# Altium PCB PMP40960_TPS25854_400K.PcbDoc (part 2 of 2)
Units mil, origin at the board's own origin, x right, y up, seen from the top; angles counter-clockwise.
Board outline 1968.5 x 1377.95 mil, 4 copper layers (Top Layer, Signal Layer 1, Signal Layer 2, Bottom Layer), stack 64.835 mil thick; 72 components, 24 nets, 181 pads, 267 vias.

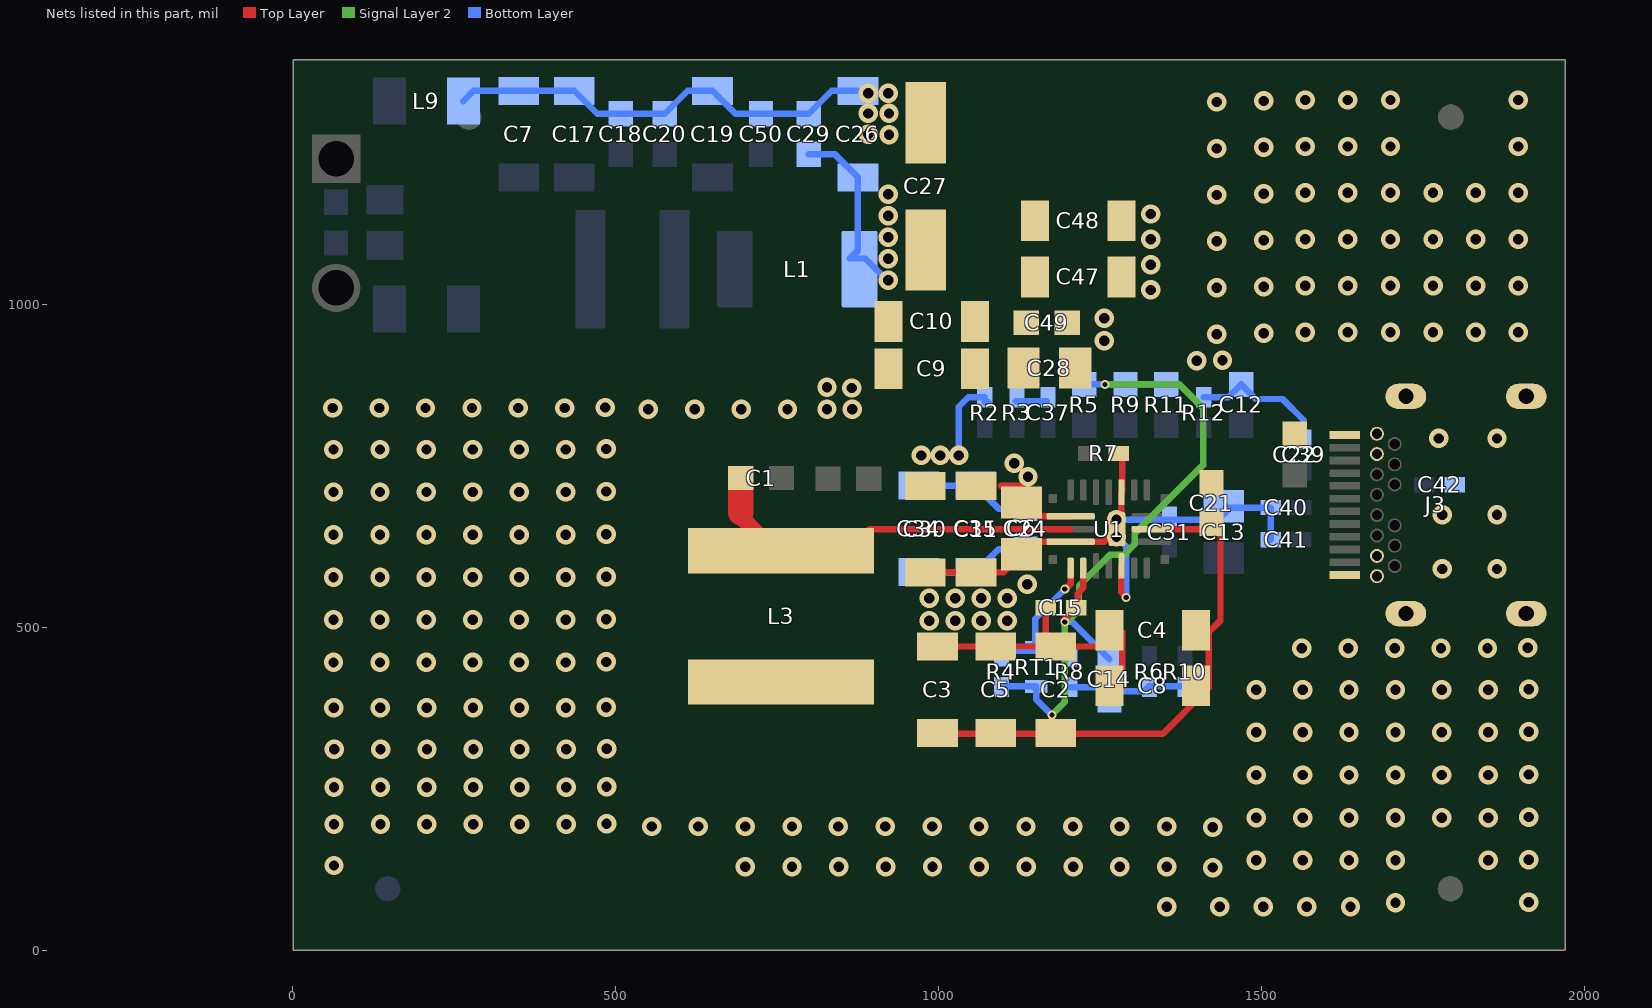
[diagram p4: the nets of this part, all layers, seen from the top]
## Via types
v1: diameter 30, hole 16, Top Layer to Bottom Layer, 246 vias
v2: diameter 14, hole 8, Top Layer to Bottom Layer, 21 vias

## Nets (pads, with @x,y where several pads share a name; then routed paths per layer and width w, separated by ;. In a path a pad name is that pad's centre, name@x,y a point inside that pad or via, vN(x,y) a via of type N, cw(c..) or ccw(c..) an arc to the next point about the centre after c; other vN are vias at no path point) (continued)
PGND: C2.2 C3.2 C4.2 C5.2 C6.2 C7.2 C8.2 C9.2 C10.2 C11.2 C12.2 C13.2 C14.2 C15.2 C17.2 C18.2 C19.2 C20.2 C21.2 C22.2 C24.2 C26.2 C27.2 C28.2 C29.2 C30.2 C31.2 C34.2 C35.2 C37.2 C39.2 C40.2 C41.2 C42.2 C47.2 C48.2 C49.2 C50.2 J3.A1 J3.A12 J3.B1 J3.B12 J3.M1 J3.M2 J3.S1 J3.S2 J3.S3 J3.S4 L9.2 R3.1 R6.1 R7.1 R8.1 R10.1 R12.1 U1.6 U1.16 U1.24 U1.25 | length 2662.7
  Top Layer w10: C30.2@979.01,584.76 1057.94,584.76 C11.2@1058.01,584.83 1100.16,584.83 C6.2@1128.01,612.69 1147.33,632.01 U1.24@1203.96,632.01 1256.13,632.01 U1.25@1275.81,651.69 1282.7,658.58 U1.16@1282.7,708.78 1284,710.08 1284,763.33 R7.1@1278.64,768.69 ; C3.2@998,469.93 C5.2@1088,469.93 C2.2@1157,469.93 ; C6.2@1143.98,598.1 C6.2@1153.56,607.68 ; C15.2@1165.38,530 1165.38,478.31 C2.2@1157,469.93 ; U1.6@1282.7,594.61 1282.7,553.97 1283.98,552.69 ; R7.1@1282.83,768.69 1282.83,771.24 1282.98,771.39 R7.1@1282.98,768.69 ; C8.2@1284.07,406 1284.07,492 1262,469.93 C2.2@1180.93,469.93 C2.2@1157,469.93
  Signal Layer 2 w10: v2@1290,543.72 v2(1290,546)
  Bottom Layer w10: L9.2@264.01,1314.01 279.94,1329.94 C7.2@349.81,1329.94 C17.2@435.81,1329.94 471.24,1294.5 C18.2@507.81,1294.5 C20.2@575.81,1294.5 611.24,1329.94 C19.2@649.81,1329.94 685.24,1294.5 C50.2@724.81,1294.5 C29.2@798.81,1294.5 834.24,1329.94 C26.2@874.81,1329.94 ; C34.2@969,585.07 C35.2@1057,585.07 1092.43,620.5 C24.2@1134,620.5 ; R3.1@1119,849.62 C37.2@1167,849.62 ; R8.1@1202,406.76 1256.75,406.76 1263,400.5 1317.13,400.5 1325,408.38 R10.1@1380,408.38 ; v1(1275.01,639.69) 1290,624.71 v2(1290,546) ; v1(1275,666) 1432,666 C13.2@1451,685 ; R12.1@1410,855.64 1448.14,855.64 C12.2@1468,875.5 1490.5,853 1532,853 1565,820 C39.2@1565,790.24 ; C13.2@1445,687 1447,685 C13.2@1451,685 ; C41.2@1513.88,635 C40.2@1513.88,685 C13.2@1451,685
  other v1: 1352.9,67.01 1434.59,67.01 1502.11,67.01 1569.63,67.01 1637.15,67.01 1706.8,73.27 1913,74.07 1424,127.76 700.21,129.01 772.73,129.01 845.25,129.01 917.78,129.01 990.3,129.01 1062.82,129.01 1135.34,129.01 1207.86,129.01 1280.24,129.23 1352.9,129.01 63.94,131.01 1491.17,139.2 1563.05,139.2 1634.92,139.2 1706.8,139.2 1850.55,139.2 1913,140 1424,190 555.67,191.25 627.55,191.25 700.21,191.25 772.88,191.25 844.26,191.25 916.92,191.25 989.59,191.25 1062.25,191.25 1134.91,191.25 1207.58,191.25 1280.24,191.25 1352.9,191.25 63.94,195.01 135.81,195.01 207.69,195.01 279.56,195.01 351.44,195.01 423.31,195.01 485.76,195.8 1491.17,205.13 1563.05,205.13 1634.92,205.13 1706.8,205.13 1778.67,205.13 1850.55,205.13 1913,205.93 63.94,252.01 135.81,252.01 207.69,252.01 279.56,252.01 351.44,252.01 423.31,252.01 485.76,252.8 1491.17,271.07 1563.05,271.07 1634.92,271.07 1706.8,271.07 1778.67,271.07 1850.55,271.07 1913,271.86 64.06,311.01 135.94,311.01 207.81,311.01 279.69,311.01 351.56,311.01 423.44,311.01 485.89,311.8 1491.17,337 1563.05,337 1634.92,337 1706.8,337 1778.67,337 1850.55,337 1913,337.79 63.48,375.01 135.36,375.01 207.23,375.01 279.11,375.01 350.98,375.01 422.86,375.01 485.31,375.8 1491.17,402.93 1563.05,402.93 1634.92,402.93 1706.8,402.93 1778.67,402.93 1850.55,402.93 1913,403.72 63.17,445.27 135.05,445.27 206.92,445.27 278.8,445.27 350.67,445.27 422.55,445.27 485,446.07 1561.69,467.01 1633.56,467.01 1705.44,467.01 1777.31,467.01 1849.19,467.01 1911.64,467.8 985.01,510 1025.33,510 1065.67,510 1106,510 63.17,511.2 135.05,511.2 206.92,511.2 278.8,511.2 350.67,511.2 422.55,511.2 485,512 985.01,544.69 1025.35,544.69 1065.68,544.69 1106.01,544.69 1137.01,566.38 63.17,577.13 135.05,577.13 206.92,577.13 278.8,577.13 350.67,577.13 422.55,577.13 485,577.93 1779,590 1864,590 63.17,643.07 135.05,643.07 206.92,643.07 278.8,643.07 350.67,643.07 422.55,643.07 485,643.86 1779,674 1864,674 63.17,709 135.05,709 206.92,709 278.8,709 350.67,709 422.55,709 485,709.79 63.17,774.93 135.05,774.93 206.92,774.93 278.8,774.93 350.67,774.93 422.55,774.93 485,775.72 1774,792 1864,792 550.25,837 622.12,837 694,837 765.88,837 827,837 865.97,837 61.81,839.01 133.69,839.01 205.56,839.01 277.44,839.01 349.31,839.01 421.19,839.01 483.64,839.8 865,870 827,871 1399,912 1439,913 1256,943 1430,953.25 1503.13,955.01 1567.21,956.38 1633.14,956.38 1699.07,956.38 1765,956.38 1830.93,956.38 1896.86,956.38 1256,978 1328,1021.83 1430,1025.12 1503.13,1026.89 1567.21,1028.25 1633.14,1028.25 1699.07,1028.25 1765,1028.25 1830.93,1028.25 1896.86,1028.25 1328,1061 1430,1097 1503.13,1098.76 1328,1100.17 1567.21,1100.12 1633.14,1100.12 1699.07,1100.12 1765,1100.12 1830.93,1100.12 1896.86,1100.12 1328,1139.33 1430,1168.88 1503.13,1170.64 1567.21,1172 1633.14,1172 1699.07,1172 1765,1172 1830.93,1172 1896.86,1172 1430,1240.75 1503.13,1242.51 1567.21,1243.88 1633.14,1243.88 1699.07,1243.88 1896.86,1243.88 922.81,1262.01 890.81,1263.01 890.81,1295.01 922.81,1295.01 1430,1312.62 1503.13,1314.39 1567.21,1315.75 1633.14,1315.75 1699.07,1315.75 1896.86,1315.75 890.81,1326.01 921.81,1326.01
SENS: C2.1 C3.1 C4.1 C5.1 C8.1 C14.1 C15.1 C21.1 L3.2 R4.2 R5.1 R9.1 R11.1 RT1.2 U1.3 U1.11 | length 2017.2
  Top Layer w10: C3.1@1003.01,335.07 1165,335.07 1165.07,335 1346.93,335 1417.93,406 1417.93,492 1436,510.07 1436,648.88 1433.18,651.69 U1.11@1328.96,651.69 ; v2(1175,364) 1175,342 C2.1@1180.93,336.07 ; v2(1195,508) 1195,509.62 1193.62,511 C15.1@1212.62,530 ; C15.1@1215.01,536.99 1215.01,551.69 ; 1215.43,552.27 1221.96,558.8 1221.96,559.26 1223.64,560.94 U1.3@1223.64,591.16
  Signal Layer 2 w10: v2(1175,364) 1195,384 v2(1195,508) 1199,508 1217,526 1217,564 1264.69,611.69 1286.61,611.69 1303.01,628.09 1303.01,644.73 1409,750.72 1409,839 1372.5,875.5 v2(1257,875.5)
  Bottom Layer w10: R4.2@1102.38,403 R4.2@1097.19,408.19 ; RT1.2@1150,403 RT1.2@1151,402 ; v2(1175,364) 1151,388 RT1.2@1151,402 ; v2(1195,508) 1206.5,508 C14.1@1264,450.5 ; R5.1@1225,875.5 v2(1257,875.5) R9.1@1289,875.5 R11.1@1352,875.5 ; R4.2@1097.19,408.19 1094.81,408.19 1096,409.38 R4.2@1097.19,408.19 ; R4.2@1097.19,408.19 RT1.2@1151,408.19 RT1.2@1151,402
SW: C1.1 L3.1 | length 536.6
  Top Layer w10: L3.1@748.2,645.27 L3.1@780.01,645.27 ; L3.1@880.01,638.27 893.44,651.69 1203.96,651.69
  Top Layer w19.68: L3.1@799.45,640.27 L3.1@821.61,640.27
  Top Layer w25: 693.52,677.2 690.01,673.69 737.25,626.46 L3.1@779.01,626.46
  Top Layer w40: 693.52,677.2 C1.1@693.52,716.84
TS: R4.1 R8.2 RT1.1 U1.2 | length 264.2
  Top Layer w10: v2(1195.01,558.69) 1196.39,558.69 1197.01,559.31 1197.01,559.56 1203.96,566.51 U1.2@1203.96,591.16
  Bottom Layer w10: R4.1@1096,456.62 1102.38,463 RT1.1@1150,463 ; v2(1195.01,558.69) 1149.32,513 1149.32,463.68 RT1.1@1150,463 ; R8.2@1202,454 1193,463 RT1.1@1150,463
VIN: C6.1 C9.1 C10.1 C11.1 C24.1 C26.1 C27.1 C28.1 C29.1 C30.1 C34.1 C35.1 C47.1 C48.1 C49.1 L1.2 R2.2 U1.22 | length 698.6
  Top Layer w10: 1095.69,718.98 1126.66,718.98 ; C6.1@1143.01,683.19 1154.83,671.38 U1.22@1203.96,671.38
  Bottom Layer w10: C29.1@798.81,1231.51 839.38,1231.51 C26.1@874.81,1196.08 874.81,1083.01 862.31,1070.51 886.09,1070.51 v1@920.81,1035.78 ; C34.1@969,718.93 C35.1@1057,718.93 1092.43,683.5 C24.1@1134,683.5 ; v1(1031.01,765.69) 1031.01,841.08 1045.57,855.64 R2.2@1071,855.64 ; R2.2@1071,848 R2.2@1077.38,848
  other v1: 1138.01,732.69 1117.01,753.69 973.01,765.69 1002.01,765.69 921.81,1036.82 921.81,1070.11 921.81,1103.41 921.81,1136.7 921.81,1170
pads on no net: FID1.1 FID2.1 FID3.1 FID4.1 FID5.1 FID6.1 J3.A2 J3.A3 J3.A8 J3.A10 J3.A11 J3.B2 J3.B3 J3.B8 J3.B10 J3.B11 U1.1 U1.12 U1.23
copper on no net: | length 36.4
  Top Layer w10: 1174.01,602.06 1176.4,604.45 ; 1328.96,671.38 1361.94,671.38

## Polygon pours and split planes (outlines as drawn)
PGND on Top Layer "TOP_LAYER_PGND_P150" (solid, remove dead copper, pour order 150): 873,1347 893,1367 1922.7,1367 1946.7,1343 1946.7,62 1916.7,32 52.7,32 23.7,61 23.7,866.21 39.49,882 798,882 873,957
no net on Top Layer "Top Layer-No Net" (solid, pour order 142): 1356,744.62
VIN on Top Layer "Top Layer-VIN" (solid, pour order 128): 906.57,1187 938,1187 956.77,1168.23 1164.77,1168.23 1185,1148 1185,1001 1162,978 1162,833 1145,816 1146,815 1146,749.89 1160,735.89 1160,685.69 1172,673.69 1172,671 1104,671 1085,690 951,690 943,698 943,765 1006,828 1006,981 1030,1005 1081,1005 1086,1010 1086,1025 1078,1033 1033,1033 1015,1015 902,1015 898,1019 898,1172
PA_BUS on Top Layer "Top Layer-PA_BUS" (solid, pour order 140): 1493.61,777 1516,777 1534.7,758.3 1589.7,758.3 1606,742 1606,730.31 1601.69,726 1582,726 1570,714 1570,646.89 1577.2,639.69 1589.69,639.69 1596,646 1604,646 1605,647 1611.73,640.27 1613,640.27 1599,626 1599,616.24 1591.76,609 1543,609 1525,627 1525,695 1507.94,712.06 1494.94,712.06 1487,720 1487,770.39
PA_BUS on Top Layer "Top Layer-PA_BUS 1" (solid, pour order 132): 1377,639 1395,639 1410,624 1410,573 1403.38,566.38 1376.31,566.38 1370,572.69 1370,617.08 1355.07,632.01 1352.55,632.01 1352.55,633.55 1358,639
SENS on Top Layer "Top Layer-SENS" (solid, pour order 130): 623.7,483.7 906.3,483.7 977,413 978,413 1015,376 1224.39,376 1235.39,365 1301,365 1362,426 1362,536.63 1414,557.49 1414,630.01 1401.01,643 1383.15,643 1371.07,655.07 1396,680 1445,680 1454,671 1454,365.16 1367.84,279 634,279 603,310 604,311 604,464
SW on Top Layer "TOP_LAYER_SW_P112" (solid, remove dead copper, pour order 112): 604.98,671.66 617.01,683.69 660.56,683.69 673.57,696.69 709.13,696.69 722.13,683.69 1085.02,683.69 1091.01,677.69 1091.02,660.69 1094.02,657.69 1094.01,647.69 1091.02,644.69 1091.02,619.69 1087.35,616.03 939.54,616.03 935.51,612 935.51,580.63 927.57,572.69 610.73,572.69 604.98,578.45
no net on Top Layer "TOP_LAYER_NONET_P088" (solid, remove dead copper, pour order 88): 634.01,683.69
no net on Top Layer "TOP_LAYER_NONET_P058" (solid, remove dead copper, pour order 58): 1349.63,691.69
no net on Top Layer "TOP_LAYER_NONET_P050" (solid, remove dead copper, pour order 50): 891.81,1331.01
PGND on Bottom Layer "BOTTOM_LAYER_PGND_P146" (solid, remove dead copper, pour order 146): 962.81,1341.01 982.81,1361.01 1921.51,1361.01 1945.51,1337.01 1945.51,56.01 1915.51,26.01 51.51,26.01 22.51,55.01 22.51,860.22 55.29,893 876.8,893 962.81,979.01
PA_BUS on Bottom Layer "Bottom Layer-PA_BUS" (solid, pour order 138): 1346.2,641 1476,641 1484,633 1484,577 1475.69,568.69 1381.31,568.69 1351,599 1345,599 1341,603 1341,636.67
VIN on Bottom Layer "Bottom Layer-VIN" (solid, pour order 136): 941,783 1147,783 1158,772 1158,665 1151,658 944,658 934,668 934,776
PGND on Bottom Layer "BOTTOM_LAYER_PGND_P144" (solid, remove dead copper, pour order 144): 235.56,1353.01 475.81,1353.01 498.81,1330.01 498.81,1329.01 581.81,1329.01 608.81,1356.01 695.81,1356.01 722.81,1329.01 806.81,1329.01 830.81,1353.01 937.81,1353.01 943.81,1347.01 943.81,1251.01 935.81,1243.01 883.81,1243.01 857.81,1269.01 706.81,1269.01 676.81,1299.01 628.29,1299.01 602.29,1273.01 484.81,1273.01 455.81,1302.01 310.81,1302.01 296.81,1288.01 296.81,1273.01 292.81,1269.01 237.81,1269.01 230.81,1276.01 230.81,1349.21
VIN on Bottom Layer "BOTTOM_LAYER_VIN_P126" (solid, remove dead copper, pour order 126): 777.81,1254.01 834.81,1254.01 859.81,1229.01 907.81,1229.01 937.81,1199.01 937.81,973.81 927,963 827,963 817.81,972.19 817.81,1186.01 801.81,1202.01 772.81,1202.01 767.81,1207.01 767.81,1245.01
NetC19_1 on Bottom Layer "BOTTOM_LAYER_NETC19_1_P124" (solid, remove dead copper, pour order 124): 552.81,1248.01 558.81,1254.01 743.81,1254.01 749.81,1248.01 749.81,960.01 740.81,951.01 561.18,951.01 552.81,959.38
NetC7_1 on Bottom Layer "BOTTOM_LAYER_NETC7_1_P122" (solid, remove dead copper, pour order 122): 232.81,1030.01 240.81,1038.01 255.81,1038.01 268.81,1051.01 268.81,1193.01 297.81,1222.01 449.81,1222.01 481.81,1254.01 531.81,1254.01 540.81,1245.01 540.81,1218.01 491.81,1169.01 491.81,960.01 480.81,949.01 404.81,949.01 395.81,958.01 395.81,1157.01 387.81,1165.01 367.81,1165.01 340,1137.2 340,954 328.01,942.01 239.19,942.01 233.81,947.39
+BAT on Bottom Layer "BOTTOM_LAYER_+BAT_P120" (solid, remove dead copper, pour order 120): 36.3,1122.01 176.81,1122.01 185.81,1113.01 185.81,952.01 171.81,938.01 37.81,938.01 17.81,958.01 17.81,1103.52
-BAT on Bottom Layer "BOTTOM_LAYER_-BAT_P114" (solid, remove dead copper, pour order 114): 47.81,1363.01 165.81,1363.01 186.81,1342.01 186.81,1153.01 170.81,1137.01 40.16,1137.01 18.81,1158.35 18.81,1334.01
PGND on Signal Layer 2 "SIGNAL_LAYER_2_PGND_P080" (solid, remove dead copper, pour order 80): 955.81,1361.01 1915.96,1361.01 1950.96,1326.01 1950.96,50.01 1925.96,25.01 39.66,25.01 24.96,39.71 24.96,861.15 55.8,892 809,892 944.6,1027.6 945.42,1350.61
PA_BUS on Signal Layer 2 "Signal Layer 2-PA_BUS" (solid, pour order 134): 1510.6,774.6 1530.4,774.6 1552,753 1552,715 1407,570 1376,570 1369,577 1369,633
PGND on Signal Layer 1 "SIGNAL_LAYER_1_PGND_P148" (solid, remove dead copper, pour order 148): 977.81,1364.01 1923.81,1364.01 1951.81,1336.01 1951.81,60.01 1919.81,28.01 38.81,28.01 25.81,41.01 25.81,862.01 52.8,889 815,889 945.52,1019.52 946.31,1332.51

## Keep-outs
Keep-Out Layer:
  text ".Layer_Name" at -1094.19,-1656.49 h60

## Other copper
Top Layer:
  pour cut-out: 1723,780 1725,778 1725,597 1721,597 1719,599 1719,777
  region net OUT: 1335,725 1335,687 1338,684 1373,684 1378,689 1378,743 1375,746 1359,746 1357,744 1357,733 1352,728 1338,728
  region: 1336,725
  pour cut-out: 942.59,460.41 942.59,580.17 928.96,563 928.96,557.3 928.96,474.04
  pour cut-out: 891.76,1011 859.81,1011 859.81,1194.87 887.67,1194.87 907.48,1194.87 882.27,1165.76 882.27,1143.88 882.27,1018.38
  pour cut-out: 906.81,1165.87
  pour cut-out: 1199.01,755.17 1204.85,761 1204.85,757.53 1205.01,757.37 1205.01,755.69
  pour cut-out: 597.92,576.71 597.92,460.83 611.55,478 611.55,483.7 611.55,563.08
  pour cut-out: 1246.01,641.01 1246.01,680.37 1248.89,683.25 1248.89,643.89
  pour cut-out: 1293.21,666.23 1293,666.44 1293,711.56 1296.09,708.47 1296.09,669.11
  pour cut-out: 1192.51,621.5 1258.65,621.5 1260.65,619.51 1193.38,619.51
  text ".Layer_Name" at -1094.19,-1656.49 h60
Signal Layer 1:
  pour cut-out: 1724,780 1725,779 1725,599 1720,599 1720,776
Bottom Layer:
  pour cut-out: 1545,766 1531,766 1531,763 1532,762 1533,763 1545,763
  pour cut-out: 1107.5,826.86 1088.5,826.86 1088.5,832 1107.5,832
  pour cut-out: 1714.86,677.5 1714.86,696.5 1720,696.5 1720,677.5
  pour cut-out: 1536.86,651.31 1536.86,670.31 1542,670.31 1542,651.31
  pour cut-out: 1544.86,704.5 1544.86,723.5 1550,723.5 1550,704.5
  pour cut-out: 1425.5,832.14 1444.5,832.14 1444.5,827 1425.5,827
  pour cut-out: 1375.5,832.14 1394.5,832.14 1394.5,827 1375.5,827
  pour cut-out: 1220.5,437.14 1239.5,437.14 1239.5,432 1220.5,432
  pour cut-out: 1344,436 1363,436 1363,430.86 1344,430.86
  pour cut-out: 206.81,972.01
  text ".Layer_Name" at -1094.19,-1656.49 h60

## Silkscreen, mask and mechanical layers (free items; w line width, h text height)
Top Overlay:
  lines w0.39: 528.2,799.68 528.39,799.87 ; 1484.71,237.68 1484.9,237.87 ; 1484.71,754.68 1484.9,754.87
  lines w10: 1134.74,554.49 ccw(c1128.01,551.69) 1135.29,551.69
  text "GND" at 176.81,1196.01 h50
  text "VIN" at 176.81,1002.01 h50
  text "H1" at 681.1,212.6 h72.83
  text "PMP40960" at 128.81,93.01 h120
  text ".Layer_Name" at -1094.19,-1656.49 h60
Bottom Overlay:
  text "GND" at 10.81,1338.01 h50 r180
  text "VIN" at 28.81,980.01 h50 r180
  text ".Layer_Name" at -1094.19,-1656.49 h60
Top Paste:
  text ".Layer_Name" at -1094.19,-1656.49 h60
Bottom Paste:
  text ".Layer_Name" at -1094.19,-1656.49 h60
Top Solder:
  circle w20: c108.81,1235.01 r9.38
  region: 549.9,317.68 504.9,317.68 504.9,225.68 549.9,225.68
  region: 595.9,214.68 595.9,259.68 503.9,259.68 503.9,214.68
  region: 610.01,775.69 610.01,820.69 518.01,820.69 518.01,775.69
  region: 909.2,214.68 909.2,259.68 817.2,259.68 817.2,214.68
  region: 1399.2,775.69 1399.2,820.69 1307.2,820.69 1307.2,775.69
  rectangle: 1463.2,471.68 1508.2,563.68
  region: 1307.2,259.68 1307.2,214.68 1399.2,214.68 1399.2,259.68
  region: 550.2,563.68 505.2,563.68 505.2,471.68 550.2,471.68
  region: 909.2,775.69 909.2,820.69 817.2,820.69 817.2,775.69
  rectangle: 504.9,728.46 549.9,820.46
  rectangle: 1141.99,694.69 1154.01,715.7
  region: 126.81,1178.01 126.81,1266.01 4.81,1266.01 4.81,1178.01
  region: 129.81,982.01 129.81,1070.01 7.81,1070.01 7.81,982.01
  rectangle: 1152.01,645.69 1174.68,658.69
  rectangle: 1152.01,625.69 1174.68,638.69
  rectangle: 1152.03,665.69 1174.66,678.69
  rectangle: 1356.88,625.68 1376.83,638.68
  rectangle: 1356.05,646 1376,659
  rectangle: 1357.05,665 1377,678
  region: 1357.03,695.1
  region: 1357.03,691.52
  region: 973.98,618.36
  lines w0.39: 513.01,248.69 623.01,248.69 ; 540.01,224.69 540.01,328.69
  text ".Layer_Name" at -1094.19,-1656.49 h60
  text ".Layer_Name" at -1094.19,-1656.49 h60
Bottom Solder:
  rectangle: 909.81,1246.01 941.81,1335.01
  rectangle: 966.81,1247.01 1017.81,1336.01
  rectangle: 1232,595 1320,711
  text ".Layer_Name" at -1094.19,-1656.49 h60
Drill Guide:
  text ".Layer_Name" at -1094.19,-1656.49 h60
M1 Board Outline:
  lines w0.39: 20.14,1348.43 20.5,1348.43 ; 0.81,0.01 0.81,1377.96 1969.31,1377.96 1969.31,0.01 0.81,0.01 ; 0.81,1968.51 0.81,1968.51
  text ".Layer_Name" at -1094.19,-1656.49 h60
M2 Board Dimensions:
  rectangle: -1671.19,-1072.99 -1546.19,-947.99
  rectangle: -1546.19,-1197.99 -1171.19,-1072.99
  lines w7: -1671.19,-1072.99 -671.19,-1072.99 ; -1671.19,-947.99 -1671.19,-1197.99 -671.19,-1197.99 -671.19,-947.99 ; -1546.19,-1197.99 -1546.19,-947.99 ; -1421.19,-1197.99 -1421.19,-947.99 ; -1171.19,-1197.99 -1171.19,-947.99 ; -921.19,-1197.99 -921.19,-947.99
  text ".Layer_Name" at -1094.19,-1656.49 h60
M3 3D STEP Top:
  text ".Layer_Name" at -1094.19,-1656.49 h60
M4 3D STEP Bottom:
  text ".Layer_Name" at -1094.19,-1656.49 h60
M5 Assembly Top:
  lines w10: -1963.19,-1728.16 4636.81,-1728.16 ; -1963.19,-1524.83 4638.81,-1524.83 ; -1963.19,-1321.49 -1963.19,-1931.49 2041.81,-1931.49 4638.81,-1931.49 4638.81,-1321.49 -1962.69,-1321.49 -1962.69,-1931.49 -387.19,-1931.49 ; 501.81,-1931.49 501.81,-1321.49 ; 1768.81,-1524.83 1768.81,-1321.49 ; 2608.81,-1524.83 2608.81,-1321.49 ; 3230.81,-1937.99 3230.81,-1735.16
  text "COMPONENTS MARKED 'DNP' SHOULD NOT BE POPULATED." at -517.69,-1116.49 h60
  text "ASSEMBLY VARIANT:" at -518.19,-1231.99 h60
  text ".VariantName" at 517.81,-1231.99 h60
  text "PCB VIEWED FROM TOP SIDE" at -1899.69,-1453.66 h60
  text "BOARD #:" at 576.81,-1453.66 h60
  text ".PRJ_Number" at 1122.31,-1453.66 h60
  text "REV:" at 1966.81,-1453.66 h60
  text ".PCB_Rev" at 2258.31,-1453.66 h60
  text "SVN REV:" at 2804.81,-1453.66 h60
  text ".VersionControl_RevNumber" at 3310.81,-1453.66 h60
  text "TID #:" at 576.81,-1656.99 h60
  text ".TID" at 1122.31,-1656.99 h60
  text "PLOT NAME =" at -1899.69,-1862.33 h60
  text ".plot_File_Name" at -1094.19,-1862.33 h60
  text "GENERATED    :" at 578.81,-1862.33 h60
  text ".Print_Date" at 1448.31,-1862.33 h60
  text ".Print_Time" at 2177.31,-1862.33 h60
  text "TEXAS INSTRUMENTS" at 3441.81,-1862.33 h60
M6 Assembly Bottom:
  lines w10: -1963.69,-1525.33 4638.31,-1525.33 ; -1961.69,-1728.66 4638.31,-1728.66 ; -555.69,-1938.49 -555.69,-1735.66 ; 66.31,-1525.33 66.31,-1321.99 ; 906.31,-1525.33 906.31,-1321.99 ; 2173.31,-1931.99 2173.31,-1321.99 ; 3062.31,-1931.99 4637.81,-1931.99 4637.81,-1321.99 -1963.69,-1321.99 -1963.69,-1931.99 633.31,-1931.99 4638.31,-1931.99 4638.31,-1321.99
  text "COMPONENTS MARKED 'DNP' SHOULD NOT BE POPULATED." at 4430.81,-1115.99 h60
  text ".VariantName" at 3386.81,-1231.99 h60
  text "ASSEMBLY VARIANT:" at 4425.81,-1231.99 h60
  text ".VersionControl_RevNumber" at -635.69,-1454.16 h60
  text "SVN REV:" at -129.69,-1454.16 h60
  text ".PCB_Rev" at 416.81,-1454.16 h60
  text "REV:" at 708.31,-1454.16 h60
  text ".PRJ_Number" at 1552.81,-1454.16 h60
  text "BOARD #:" at 2098.31,-1454.16 h60
  text "PCB VIEWED FROM BOTTOM SIDE" at 4574.81,-1454.16 h60
  text ".TID" at 1552.81,-1657.49 h60
  text "TID #:" at 2098.31,-1657.49 h60
  text "TEXAS INSTRUMENTS" at -766.69,-1862.83 h60
  text ".Print_Time" at 497.81,-1862.83 h60
  text ".Print_Date" at 1226.81,-1862.83 h60
  text "GENERATED    :" at 2096.31,-1862.83 h60
  text ".plot_File_Name" at 3769.31,-1862.83 h60
  text "PLOT NAME =" at 4574.81,-1862.83 h60
M9 Title Sheet:
  drawing of 57 lines, arcs and shapes, not listed
  text "1" at -931.35,7238.51 h70
  text "2" at 1564.31,7238.51 h70
  text "3" at 4053.65,7238.51 h70
  text "4" at 6560.32,7238.51 h70
  text "5" at 9059.31,7238.51 h70
  text "6" at 11564.31,7238.51 h70
  text "A" at -2087.69,6095.51 h70
  text "A" at 12712.31,6095.51 h70
  text "B" at -2087.69,3715.51 h70
  text "B" at 12712.31,3715.51 h70
  text "C" at -2087.69,1340.51 h70
  text "C" at 12712.31,1340.51 h70
  text "PROJECT TITLE:" at 9672.31,-520.49 h45
  text ".PRJ_Title" at 9722.31,-653.82 h70
  text "DESIGNED FOR:" at 9672.31,-821.49 h45
  text ".PRJ_Customer" at 9722.31,-961.49 h70
  text "D" at -2087.69,-1029.49 h70
  text "D" at 12712.31,-1029.49 h70
  text "FILE NAME:" at 9672.31,-1121.49 h45
  text ".PCB_File_Name_No_Path" at 9722.31,-1241.49 h70
  text "Texas Instruments (TI) and/or its licensors do not warrant the accuracy or completeness of this specification" at 4702.81,-1403.33 h45
  text "ENGINEER:" at 9672.31,-1411.49 h45
  text "LAYOUT BY:" at 11177.31,-1411.49 h45
  text "or any information contained therein. TI and/or its licensors do not warrant that this design will meet" at 4657.83,-1516 h45
  text ".PRJ_Engineer" at 9722.31,-1566.48 h70
  text ".PCB_Layout" at 11227.81,-1566.48 h70
  text "the specifications, will be suitable for your application or fit for any particular purpose, or will operate in" at 4657.83,-1628.66 h45
  text ".Layer_Name" at -1094.19,-1656.49 h60
  text "ALTIUM DESIGNER VERSION:" at 11177.31,-1721.49 h45
  text "an implementation. TI and/or its licensors do not warrant that the design is production worthy. You should" at 4657.83,-1741.33 h45
  text "completely validate and test your design implementation to confirm the system functionality for your application." at 4702.81,-1853.99 h45
  text ".print_Scale" at 9722.31,-1854.82 h70
  text ".Application_BuildNumber" at 11227.81,-1854.82 h70
  text "1" at -931.35,-2061.49 h70
  text "2" at 1564.31,-2061.49 h70
  text "3" at 4053.65,-2061.49 h70
  text "4" at 6560.32,-2061.49 h70
  text "5" at 9059.31,-2061.49 h70
  text "6" at 11564.31,-2061.49 h70
M10 Fab Notes:
  drawing of 189 lines, arcs and shapes, not listed
  text "DESIGN INFORMATION" at 10710.83,5558.18 h60
  text "MIN. TRACK WIDTH:" at 10066.27,5426.06 h60
  text "8" at 11162.51,5426.06 h60
  text "MIL" at 11317.27,5426.06 h60
  text "MIN. CLEARANCE:" at 10066.27,5301.93 h60
  text "0.2" at 11102.51,5301.93 h60
  text "mm" at 11317.27,5301.93 h60
  text "MIN. VIA PAD SIZE:" at 10066.27,5177.8 h60
  text "24" at 11132.52,5177.81 h60
  text "MIL" at 11317.27,5177.8 h60
  text "0.05mm (2MIL)" at 10761.27,5047.9 h60
  text "MINIMUM ANNULAR RING" at 9737.04,5039.68 h60
  text "EXTERNAL" at 11469.27,5039.68 h60
  text "PER" at 9937.04,4929.56 h60
  text "IPC-D-275 CLASS 2 LEVEL C" at 10157.04,4929.55 h60
  text "MIL, HOLES" at 11645.27,4829.08 h60
  text "+/-" at 11252.81,4820.49 h60
  text "+/-" at 12106.81,4820.49 h60
  text "REGISTRATION TOLERANCES:" at 9737.04,4819.43 h60
  text "METAL" at 10936.81,4819.43 h60
  text "5" at 11513.01,4819.43 h60
  text "3" at 12346.01,4819.43 h60
  text "MIL" at 12462.27,4819.43 h60
  text "HOLE SIZE TOLERANCE (UNLESS OTHERWISE SPECIFIED):" at 9737.04,4721.11 h60
  text "+/-" at 12106.81,4718.24 h60
  text "3" at 12346.01,4717.18 h60
  text "MIL" at 12462.27,4717.17 h60
  text "MATERIAL:" at 9662.27,4579.53 h60
  text "FR-4 High Tg" at 10648.71,4451 h60
  text "X" at 10504.28,4443.01 h60
  text "FR-408" at 10083.27,4438.5 h60
  text "OTHER" at 11571.27,4438.5 h60
  text "62 MIL (1.6mm) +/-10%" at 10403.37,4295.47 h60
  text "X" at 10283.28,4293.01 h60
  text "THICKNESS:" at 9737.04,4287.25 h60
  text "OTHER" at 11688.27,4287.25 h60
  text "TOLERANCE:" at 9737.04,4148.93 h60
  text "X" at 10585.28,4148.93 h60
  text "ANSI IPC-6012 TYPE 3 CLASS 2" at 10763.29,4148.93 h60
  text "OTHER +/-" at 10763.27,4004.74 h60
  text "BOW & TWIST:" at 9737.04,3859.55 h60
  text "X" at 10585.28,3859.55 h60
  text "ANSI IPC-6012 TYPE 3 CLASS 2" at 10763.29,3859.55 h60
  text "OTHER +/-" at 10763.27,3712.86 h60
  text "DRILLING:" at 9662.27,3582.24 h60
  text "NC_DRILL FILES" at 11423.27,3477.05 h60
  text "REFERENCE:" at 9737.04,3473.11 h60
  text "X" at 10394.28,3473.01 h60
  text "AS SHOWN" at 10572.27,3473.11 h60
  text "X" at 11295.28,3473.11 h60
  text "OTHER" at 11721.27,3330.86 h60
  text "PTH COPPER THICKNESS:" at 9736.72,3327.33 h60
  text "X" at 10875.95,3327.33 h60
  text "20-30 um" at 11003.95,3327.33 h60
  text "BOARD FINISH:" at 9662.27,3179.73 h60
  text "SILKSCREEN:" at 9817.49,3069.61 h60
  text "X" at 10775.28,3069.61 h60
  text "TOP" at 10892.27,3069.61 h60
  text "X" at 11285.28,3069.61 h60
  text "BOTTOM" at 11403.27,3069.61 h60
  text "SILKSCREEN COLOR:" at 9817.49,2914.42 h60
  text "X" at 10774.28,2914.42 h60
  text "WHITE" at 10892.27,2914.42 h60
  text "OTHER" at 11403.27,2914.42 h60
  text "X" at 10905.28,2770.97 h60
  text "GREEN" at 11023.27,2770.97 h60
  text "OTHER" at 11641.27,2770.97 h60
  text "SOLDER RESIST COLOR:" at 9817.49,2764.1 h60
  text "X" at 10905.28,2616.72 h60
  text "MATTE" at 11023.27,2616.72 h60
  text "SEMI-GLOSS" at 11640.81,2616.08 h60
  text "IMMERSION GOLD (ENIG)" at 10723.27,2443.95 h60
  text "ENEPIG" at 12060.81,2436.73 h60
  text "SURFACE FINISH:" at 9662.27,2435.73 h60
  text "X" at 10545.28,2435.73 h60
  text "IMM. TIN/SILVER OR EQUIV" at 9991.81,2298.41 h60
  text "OTHER" at 11423.27,2294.47 h60
  text "ARRAY/PANEL:" at 9662.27,2139.1 h60
  text "CUT AND TRIM PER M1 BOARD OUTLINE" at 10723.27,2130.87 h60
  text "N.C. ROUTE" at 10723.27,1994.91 h60
  text "X" at 11411.28,1994.91 h60
  text "V. SCORE" at 11589.27,1994.91 h60
  text "CERTIFICATION:" at 9662.27,1865.78 h60
  text "MATERIALS AND WORKMANSHIP FOR ALL PCBS" at 10387.27,1865.78 h60
  text "TO MEET OR EXCEED THE REQUIREMENTS OF:" at 10387.27,1771.72 h60
  text "X" at 10024.78,1643.09 h60
  text "ANSI IPC-A-600F CLASS ->" at 10152.77,1643.09 h60
  text "X" at 11800.78,1643.09 h60
  text "2" at 11910.77,1643.09 h60
  text "1" at 11595.77,1641.59 h60
  text "3" at 12264.77,1641.59 h60
  text "X" at 10836.78,1495.4 h60
  text "RoHS" at 10964.77,1495.4 h60
  text "OTHER" at 11609.18,1495.4 h60
  text "PER ORDER" at 12006.23,1495.4 h60
  text "ALL BOARDS MUST MEET OR EXCEED UL94-V0 REQUIREMENTS." at 9689.81,1341.57 h60
  text "PCB MUST BEAR THE UL94V-0 UL REGISTERED MATERIAL ID NUMBER" at 9689.81,1225.51 h60
  text "ADDITIONAL REQUIREMENTS:" at 9662.27,1056.09 h60
  text "MICROSECTION:" at 9737.04,948.96 h60
  text "YES" at 10642.77,948.96 h60
  text "REQUIRED" at 11504.27,804.63 h60
  text "BARE BOARD ELEC. TEST:" at 9737.04,801.77 h60
  text "NONE" at 11042.77,801.77 h60
  text "X" at 11386.28,801.77 h60
  text "PER ORDER" at 12096.27,801.77 h60
  text "XX MIL VIAS REQUIRE NON-CONDUCTIVE FILL AND PLANARIZE" at 9905.19,596.83 h59
  text "XX MIL VIAS REQUIRE CONDUCTIVE FILL AND PLANARIZE" at 9913.19,492.85 h60
  text "OUTER XX MIL TRACES REQUIRE 50 OHM SINGLE-ENDED IMPEDANCE" at 9912.2,329.46 h58
  text "LAYER 2 & 3 (INNER LAYERS) XX MIL WIDE, XX MIL SPACE / TRACES REQUIRE 100 OHM DIFFERENTIAL IMPEDANCE" at 9904.2,93.75 h60
  text ".Layer_Name" at -1094.19,-1656.49 h60
M11 Gerber Information:
  lines w10: -1963.19,-1728.16 4636.81,-1728.16 ; -1963.19,-1524.83 4638.81,-1524.83 ; -1963.19,-1321.49 -1963.19,-1931.49 2041.81,-1931.49 4638.81,-1931.49 4638.81,-1321.49 -1962.69,-1321.49 -1962.69,-1931.49 -387.19,-1931.49 ; 501.81,-1931.49 501.81,-1321.49 ; 1768.81,-1524.83 1768.81,-1321.49 ; 2608.81,-1524.83 2608.81,-1321.49 ; 3230.81,-1937.99 3230.81,-1735.16
  text "ALL ARTWORK VIEWED FROM TOP SIDE" at -1899.69,-1453.66 h60
  text "BOARD #:" at 576.81,-1453.66 h60
  text ".PRJ_Number" at 1122.31,-1453.66 h60
  text "REV:" at 1966.81,-1453.66 h60
  text ".PCB_Rev" at 2258.31,-1453.66 h60
  text "SVN REV:" at 2804.81,-1453.66 h60
  text ".VersionControl_RevNumber" at 3310.81,-1453.66 h60
  text "LAYER NAME =" at -1899.69,-1656.49 h60
  text "TID #:" at 576.81,-1656.99 h60
  text ".TID" at 1122.31,-1656.99 h60
  text "PLOT NAME =" at -1899.69,-1862.33 h60
  text ".plot_File_Name" at -1094.19,-1862.33 h60
  text "GENERATED    :" at 578.81,-1862.33 h60
  text ".Print_Date" at 1448.31,-1862.33 h60
  text ".Print_Time" at 2177.31,-1862.33 h60
  text "TEXAS INSTRUMENTS" at 3441.81,-1862.33 h60
M12 Stackup:
  drawing of 243 lines, arcs and shapes, not listed
  text "Layer" at 8140.41,5569.45 h60
  text "Name" at 8550.32,5569.45 h60
  text "Material" at 9490.06,5569.45 h60
  text "Thickness" at 10349.83,5569.45 h60
  text "Constant" at 10999.66,5569.45 h60
  text "Board Layer Stack" at 11569.52,5569.45 h60
  text "1" at 8140.41,5449.45 h60
  text "Top Overlay" at 8550.32,5449.45 h60
  text "2" at 8140.41,5329.45 h60
  text "Top Solder" at 8550.32,5329.45 h60
  text "Solder Resist" at 9490.06,5329.45 h60
  text "0.40mil" at 10349.83,5329.45 h60
  text "3.5" at 10999.66,5329.45 h60
  text "3" at 8140.41,5209.45 h60
  text "Top Layer" at 8550.32,5209.45 h60
  text "Copper" at 9490.06,5209.45 h60
  text "1.40mil" at 10349.83,5209.45 h60
  text "4" at 8140.41,5089.45 h60
  text "Signal Layer 1" at 8550.32,5089.45 h60
  text "Copper" at 9490.06,5089.45 h60
  text "1.42mil" at 10349.83,5089.45 h60
  text "5" at 8140.41,4969.45 h60
  text "Signal Layer 2" at 8550.32,4969.45 h60
  text "Copper" at 9490.06,4969.45 h60
  text "1.42mil" at 10349.83,4969.45 h60
  text "6" at 8140.41,4849.45 h60
  text "Dielectric1" at 8550.32,4849.45 h60
  text "FR-4" at 9490.06,4849.45 h60
  text "59.20mil" at 10349.83,4849.45 h60
  text "4.8" at 10999.66,4849.45 h60
  text "7" at 8140.41,4729.45 h60
  text "Bottom Layer" at 8550.32,4729.45 h60
  text "Copper" at 9490.06,4729.45 h60
  text "1.40mil" at 10349.83,4729.45 h60
  text "8" at 8140.41,4609.45 h60
  text "Bottom Solder" at 8550.32,4609.45 h60
  text "Solder Resist" at 9490.06,4609.45 h60
  text "0.40mil" at 10349.83,4609.45 h60
  text "3.5" at 10999.66,4609.45 h60
  text "9" at 8140.41,4489.45 h60
  text "Bottom Overlay" at 8550.32,4489.45 h60
  text ".Layer_Name" at -1094.19,-1656.49 h60
M13 Component Bodies Top:
  text ".Layer_Name" at -1094.19,-1656.49 h60
M14 Component Bodies Bottom:
  text ".Layer_Name" at -1094.19,-1656.49 h60
M15 Courtyards Top:
  text ".Layer_Name" at -1094.19,-1656.49 h60
M16 Courtyards Bottom:
  text ".Layer_Name" at -1094.19,-1656.49 h60
Drill Drawing:
  circle w10: c3692.53,2881.53 r27.63
  lines w10: 3664.9,2729.59 3720.15,2729.59 3720.15,2784.84 3664.9,2784.84 3664.9,2729.59 ; 3664.9,2992.04 3678.71,2992.04 3678.71,2978.23 3706.34,2978.23 3706.34,2992.04 3720.15,2992.04 3720.15,3019.67 3706.34,3019.67 3706.34,3033.48 3678.71,3033.48 3678.71,3019.67 3664.9,3019.67 3664.9,2992.04 ; 3664.9,3157.8 3720.15,3157.8 3692.53,3102.55 3664.9,3157.8 ; 3664.9,3240.68 3678.71,3240.68 3692.53,3226.87 3706.34,3240.68 3720.15,3240.68 3706.34,3254.49 3720.15,3268.31 3706.34,3268.31 3692.53,3282.12 3678.71,3268.31 3664.9,3268.31 3678.71,3254.49 3664.9,3240.68
  lines w12: 3614.81,2692.29 6846.3,2692.29 ; 3614.81,3313.89 6846.3,3313.89 ; 3952.67,2567.97 3952.67,3438.21 ; 4284.67,2567.97 4284.67,3438.21 ; 4921.24,2567.97 4921.24,3438.21 ; 5180.38,2567.97 5180.38,3438.21 ; 5555.53,2567.97 5555.53,3438.21 ; 6279.87,2567.97 6279.87,3438.21 ; 3614.81,2567.97 6846.3,2567.97 6846.3,3438.21 3614.81,3438.21 3614.81,2567.97
  text "Symbol" at 3689.4,3351.19 h72
  text "Quantity" at 3989.97,3351.19 h72
  text "Finished Hole Size" at 4321.97,3351.19 h72
  text "Plated" at 4958.53,3351.19 h72
  text "Hole Type" at 5217.67,3351.19 h72
  text "Drill Layer Pair" at 5592.83,3351.19 h72
  text "Hole Tolerance" at 6317.16,3351.19 h72
  text "21" at 3989.97,3226.87 h60
  text "8.00mil (0.203mm)" at 4321.97,3226.87 h60
  text "PTH" at 4958.53,3226.87 h60
  text "Round" at 5217.67,3226.87 h60
  text "Top Layer - Bottom Layer" at 5592.83,3226.87 h60
  text "14" at 3989.97,3102.55 h60
  text "15.75mil (0.400mm)" at 4321.97,3102.55 h60
  text "PTH" at 4958.53,3102.55 h60
  text "Round" at 5217.67,3102.55 h60
  text "Top Layer - Bottom Layer" at 5592.83,3102.55 h60
  text "246" at 3989.97,2978.23 h60
  text "16.00mil (0.406mm)" at 4321.97,2978.23 h60
  text "PTH" at 4958.53,2978.23 h60
  text "Round" at 5217.67,2978.23 h60
  text "Top Layer - Bottom Layer" at 5592.83,2978.23 h60
  text "2" at 3989.97,2853.91 h60
  text "55.12mil (1.400mm)" at 4321.97,2853.91 h60
  text "PTH" at 4958.53,2853.91 h60
  text "Round" at 5217.67,2853.91 h60
  text "Top Layer - Bottom Layer" at 5592.83,2853.91 h60
  text "4" at 3989.97,2729.59 h60
  text "23.62mil (0.600mm)" at 4321.97,2729.59 h60
  text "PTH" at 4958.53,2729.59 h60
  text "Slot" at 5217.67,2729.59 h60
  text "Top Layer - Bottom Layer" at 5592.83,2729.59 h60
  text "287 Total" at 3989.97,2605.27 h60
  text "Slot definitions :" at 3689.4,2518.24 h60
  text "Routed Path Length" at 4140.12,2518.24 h60
  text "= Calculated from tool start centre position to tool end centre position." at 4679.86,2518.24 h60
  text "Hole Length" at 4140.12,2468.51 h60
  text "= Routed Path Length + Tool Size = Slot length as defined in the PCB layout" at 4480.06,2468.51 h60
  text ".Layer_Name" at -1094.19,-1656.49 h60
M17 Embedded Cavity:
  text ".Layer_Name" at -1094.19,-1656.49 h60
M18 Embedded Assembly:
  text ".Layer_Name" at -1094.19,-1656.49 h60
M19 Embedded Keepout:
  text ".Layer_Name" at -1094.19,-1656.49 h60

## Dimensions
0.81,0.01 to 0.81,1377.96 on M2 Board Dimensions
-1671.19,-1197.99 to -671.19,-1197.99 on M2 Board Dimensions
1969.31,0.01 to 0.81,0.01 on M2 Board Dimensions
